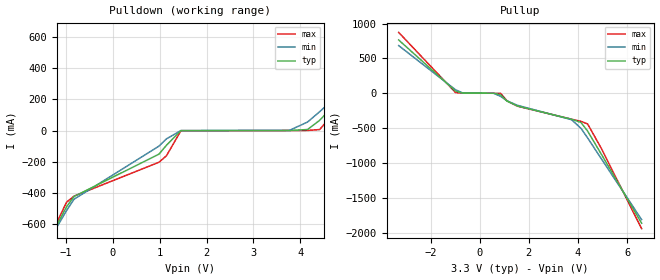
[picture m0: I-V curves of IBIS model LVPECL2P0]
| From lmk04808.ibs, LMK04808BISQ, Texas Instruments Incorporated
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|   Model LVPECL2P0V
[Model]   LVPECL2P0
Model_type   Output
Polarity   Non-Inverting
Vmeas = 1.99
Vref = 1.99
Cref = .3pF
Rref = 240
|   typ   min   max
|   (nom PVT)   (fast PVT)   (slow PVT)
C_comp   0.2109p   0.1807p   0.2310p
|C_comp (Low state)   0.2109p   0.1807p   0.2310p
|C_comp (High state)   0.9933p   0.9197p   1.0724p
[Voltage Range]   3.3   3.15   3.45
[Temperature Range]   45   125   -40
[Pullup Reference]   3.3   3.15   3.45
[Pulldown Reference]   0   0   0
[Power Clamp Reference]   3.3   3.15   3.45
[GND Clamp Reference]   0   0   0
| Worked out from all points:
|   slope of the pulldown table from 0 to 0.495 V, typ, clamps not added: 7.42 ohm
[Pulldown]
|   Voltage   I(typ)   I(min)   I(max)
-3.3V     -1.869A    -1.737A    -2.051A
-1.28V    -652.5mA   -661.4mA   -639.7mA
-983.4mV  -485.5mA   -510mA     -456.6mA
-825mV    -421.3mA   -438.6mA   -419mA
986.7mV   -150.5mA   -99.33mA   -202.4mA
1.145V    -93.97mA   -53.27mA   -161.1mA
1.452V    -583uA     -287.8uA   -1.99mA
3.769V    8.124uA    1.31mA     128.1nA
4.155V    6.485mA    54.36mA    475.7uA
4.412V    65.2mA     120mA      6.277mA
5.145V    293.7mA    319.5mA    257.9mA
6.59V     761.2mA    723.2mA    811.3mA
[Pullup]
|   Voltage   I(typ)   I(min)   I(max)
-3.3V     764.4mA    683.9mA    873mA
-983.4mV  30.09mA    49.29mA    9.236mA
-686.4mV  508.5uA    3.353mA    377.6uA
561mV     -3.193uA   -260.9uA   -15.17nA
848.1mV   -23.41mA   -44.36mA   -1.6mA
1.115V    -113.3mA   -109.9mA   -110.4mA
1.531V    -182.7mA   -172.8mA   -185.6mA
3.739V    -372.4mA   -379.6mA   -372.9mA
4.125V    -420.2mA   -504.9mA   -403.5mA
4.392V    -543.2mA   -640.9mA   -440.5mA
4.966V    -883.9mA   -948.6mA   -801.6mA
6.59V     -1.865A    -1.813A    -1.943A
[Ramp]
R_load = 240
|   typ   min   max
dV/dt_r   0.669407/5.08194e-11   0.660633/6.67586e-11   0.676564/4.24188e-11
dV/dt_f   0.66946/6.18152e-11   0.660583/7.75013e-11   0.676594/5.50565e-11
